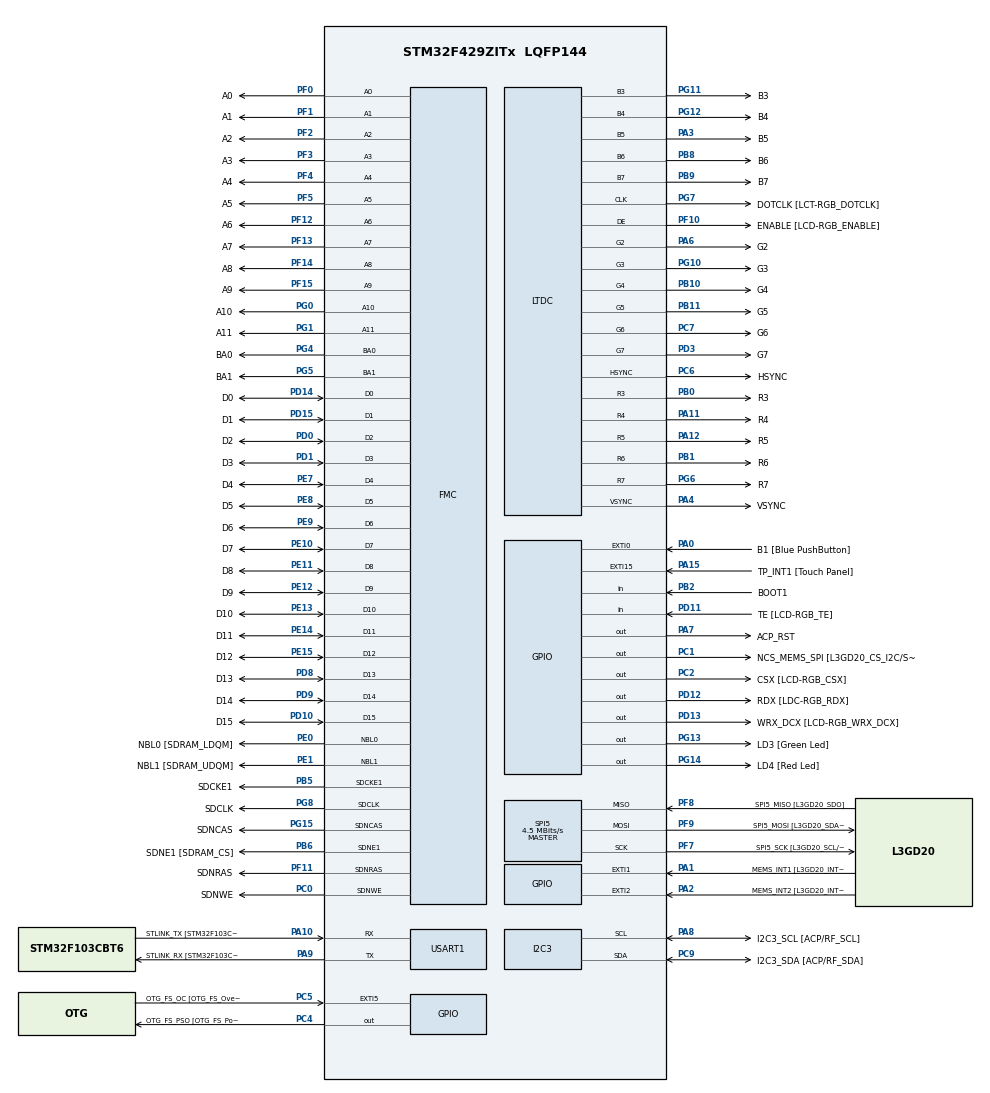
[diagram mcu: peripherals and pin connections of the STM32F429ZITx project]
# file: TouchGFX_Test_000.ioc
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DMA2D.ColorMode=DMA2D_OUTPUT_RGB565
FMC.CASLatency1=FMC_SDRAM_CAS_LATENCY_3
FMC.ExitSelfRefreshDelay1=7
FMC.LoadToActiveDelay1=2
FMC.RCDDelay1=2
FMC.RPDelay1=2
FMC.RPDelay2=2
FMC.ReadBurst1=FMC_SDRAM_RBURST_DISABLE
FMC.ReadPipeDelay1=FMC_SDRAM_RPIPE_DELAY_1
FMC.ReadPipeDelay2=FMC_SDRAM_RPIPE_DELAY_1
FMC.RowCycleDelay1=7
FMC.RowCycleDelay2=7
FMC.SDClockPeriod1=FMC_SDRAM_CLOCK_PERIOD_2
FMC.SDClockPeriod2=FMC_SDRAM_CLOCK_PERIOD_2
FMC.SelfRefreshTime1=4
FMC.WriteRecoveryTime1=3
FREERTOS.Tasks01=defaultTask,0,4096,StartDefaultTask,Default,NULL,Dynamic,NULL,NULL
FREERTOS.configCHECK_FOR_STACK_OVERFLOW=2
FREERTOS.configTOTAL_HEAP_SIZE=32768
FREERTOS.configUSE_APPLICATION_TASK_TAG=1
FREERTOS.configUSE_COUNTING_SEMAPHORES=1
FREERTOS.configUSE_IDLE_HOOK=1
FREERTOS.configUSE_MALLOC_FAILED_HOOK=1
FREERTOS.configUSE_RECURSIVE_MUTEXES=1
LTDC.ActiveH=320
LTDC.ActiveW=240
LTDC.Alpha_L0=255
LTDC.BlendingFactor1_L0=LTDC_BLENDING_FACTOR1_CA
LTDC.BlendingFactor2_L0=LTDC_BLENDING_FACTOR2_CA
LTDC.FBStartAdress_L0=0xD0000000
LTDC.HBP=20
LTDC.HFP=10
LTDC.HSync=10
LTDC.ImageHeight_L0=320
LTDC.ImageWidth_L0=240
LTDC.Layers=0
LTDC.PixelFormat_L0=LTDC_PIXEL_FORMAT_RGB565
LTDC.VFP=4
LTDC.VSync=2
LTDC.WindowX1_L0=240
LTDC.WindowY1_L0=320
Mcu.Family=STM32F4
Mcu.Name=STM32F429ZITx
Mcu.Package=LQFP144
NVIC.DMA2D_IRQn=true\:5\:0\:true\:false\:true\:true\:true\:true
NVIC.LTDC_IRQn=true\:5\:0\:true\:false\:true\:true\:true\:true
NVIC.PriorityGroup=NVIC_PRIORITYGROUP_4
NVIC.TIM6_DAC_IRQn=true\:0\:0\:false\:false\:true\:false\:false\:true
NVIC.TimeBase=TIM6_DAC_IRQn
NVIC.TimeBaseIP=TIM6
PA0/WKUP.GPIO_Label=B1 [Blue PushButton]
PA0/WKUP.GPIO_ModeDefaultEXTI=GPIO_MODE_EVT_RISING
PA0/WKUP.GPIO_PuPd=GPIO_NOPULL
PA0/WKUP.Signal=GPXTI0
PA1.GPIO_Label=MEMS_INT1 [L3GD20_INT1]
PA1.GPIO_ModeDefaultEXTI=GPIO_MODE_EVT_RISING
PA1.GPIO_PuPd=GPIO_NOPULL
PA1.Signal=GPXTI1
PA10.GPIO_Label=STLINK_TX [STM32F103CBT6_PA2]
PA10.Mode=Asynchronous
PA10.Signal=USART1_RX
PA11.GPIO_Label=R4
PA11.GPIO_Mode=GPIO_MODE_AF_PP
PA11.GPIO_PuPd=GPIO_NOPULL
PA11.GPIO_Speed=GPIO_SPEED_FREQ_LOW
PA11.Mode=RGB565
PA11.Signal=LTDC_R4
PA12.GPIO_Label=R5
PA12.GPIO_Mode=GPIO_MODE_AF_PP
PA12.GPIO_PuPd=GPIO_NOPULL
PA12.GPIO_Speed=GPIO_SPEED_FREQ_LOW
PA12.Mode=RGB565
PA12.Signal=LTDC_R5
PA13.GPIO_Label=SWDIO
PA13.Mode=Serial_Wire
PA13.Signal=SYS_JTMS-SWDIO
PA14.GPIO_Label=SWCLK
PA14.Mode=Serial_Wire
PA14.Signal=SYS_JTCK-SWCLK
PA15.GPIO_Label=TP_INT1 [Touch Panel]
PA15.GPIO_ModeDefaultEXTI=GPIO_MODE_EVT_RISING
PA15.GPIO_PuPd=GPIO_NOPULL
PA15.Signal=GPXTI15
PA2.GPIO_Label=MEMS_INT2 [L3GD20_INT2]
PA2.GPIO_ModeDefaultEXTI=GPIO_MODE_EVT_RISING
PA2.GPIO_PuPd=GPIO_NOPULL
PA2.Signal=GPXTI2
PA3.GPIO_Label=B5
PA3.GPIO_Mode=GPIO_MODE_AF_PP
PA3.GPIO_PuPd=GPIO_NOPULL
PA3.GPIO_Speed=GPIO_SPEED_FREQ_LOW
PA3.Mode=RGB565
PA3.Signal=LTDC_B5
PA4.GPIO_Label=VSYNC
PA4.GPIO_Mode=GPIO_MODE_AF_PP
PA4.GPIO_PuPd=GPIO_NOPULL
PA4.GPIO_Speed=GPIO_SPEED_FREQ_LOW
PA4.Mode=RGB565
PA4.Signal=LTDC_VSYNC
PA6.GPIO_Label=G2
PA6.GPIO_Mode=GPIO_MODE_AF_PP
PA6.GPIO_PuPd=GPIO_NOPULL
PA6.GPIO_Speed=GPIO_SPEED_FREQ_LOW
PA6.Mode=RGB565
PA6.Signal=LTDC_G2
PA7.GPIO_Label=ACP_RST
PA7.GPIO_Mode=GPIO_MODE_OUTPUT_PP
PA7.GPIO_PuPd=GPIO_NOPULL
PA7.GPIO_Speed=GPIO_SPEED_FREQ_LOW
PA7.Signal=GPIO_Output
PA8.GPIO_Label=I2C3_SCL [ACP/RF_SCL]
PA8.GPIO_Mode=GPIO_MODE_AF_OD
PA8.GPIO_Pu=GPIO_PULLUP
PA8.GPIO_PuPd=GPIO_NOPULL
PA8.GPIO_Speed=GPIO_SPEED_FREQ_LOW
PA8.Mode=I2C
PA8.Signal=I2C3_SCL
PA9.GPIO_Label=STLINK_RX [STM32F103CBT6_PA3]
PA9.Mode=Asynchronous
PA9.Signal=USART1_TX
PB0.GPIO_Label=R3
PB0.GPIO_Mode=GPIO_MODE_AF_PP
PB0.GPIO_PuPd=GPIO_NOPULL
PB0.GPIO_Speed=GPIO_SPEED_FREQ_LOW
PB0.Mode=RGB565
PB0.Signal=LTDC_R3
PB1.GPIO_Label=R6
PB1.GPIO_Mode=GPIO_MODE_AF_PP
PB1.GPIO_PuPd=GPIO_NOPULL
PB1.GPIO_Speed=GPIO_SPEED_FREQ_LOW
PB1.Mode=RGB565
PB1.Signal=LTDC_R6
PB10.GPIO_Label=G4
PB10.GPIO_Mode=GPIO_MODE_AF_PP
PB10.GPIO_PuPd=GPIO_NOPULL
PB10.GPIO_Speed=GPIO_SPEED_FREQ_LOW
PB10.Mode=RGB565
PB10.Signal=LTDC_G4
PB11.GPIO_Label=G5
PB11.GPIO_Mode=GPIO_MODE_AF_PP
PB11.GPIO_PuPd=GPIO_NOPULL
PB11.GPIO_Speed=GPIO_SPEED_FREQ_LOW
PB11.Mode=RGB565
PB11.Signal=LTDC_G5
PB12.GPIO_Label=OTG_HS_ID
PB12.GPIO_Mode=GPIO_MODE_AF_PP
PB12.GPIO_PuPd=GPIO_NOPULL
PB12.GPIO_Speed=GPIO_SPEED_FREQ_LOW
PB12.Signal=USB_OTG_HS_ID
PB13.GPIO_Label=VBUS_HS
PB13.GPIO_Mode=GPIO_MODE_INPUT
PB13.GPIO_PuPd=GPIO_NOPULL
PB13.Signal=USB_OTG_HS_VBUS
PB14.GPIO_Label=OTG_HS_DM
PB14.GPIO_Mode=GPIO_MODE_AF_PP
PB14.GPIO_PuPd=GPIO_NOPULL
PB14.GPIO_Speed=GPIO_SPEED_FREQ_LOW
PB14.Signal=USB_OTG_HS_DM
PB15.GPIO_Label=OTG_HS_DP
PB15.GPIO_Mode=GPIO_MODE_AF_PP
PB15.GPIO_PuPd=GPIO_NOPULL
PB15.GPIO_Speed=GPIO_SPEED_FREQ_LOW
PB15.Signal=USB_OTG_HS_DP
PB2/BOOT1.GPIO_Label=BOOT1
PB2/BOOT1.GPIO_Mode=GPIO_MODE_INPUT
PB2/BOOT1.GPIO_PuPd=GPIO_NOPULL
PB2/BOOT1.Signal=GPIO_Input
PB5.GPIO_Label=SDCKE1
PB5.GPIO_Mode=GPIO_MODE_AF_PP
PB5.GPIO_PuPd=GPIO_NOPULL
PB5.GPIO_Speed=GPIO_SPEED_FREQ_VERY_HIGH
PB5.Mode=SdramChipSelect2_1
PB5.Signal=FMC_SDCKE1
PB6.GPIO_Label=SDNE1 [SDRAM_CS]
PB6.GPIO_Mode=GPIO_MODE_AF_PP
PB6.GPIO_PuPd=GPIO_NOPULL
PB6.GPIO_Speed=GPIO_SPEED_FREQ_VERY_HIGH
PB6.Mode=SdramChipSelect2_1
PB6.Signal=FMC_SDNE1
PB8.GPIO_Label=B6
PB8.GPIO_Mode=GPIO_MODE_AF_PP
PB8.GPIO_PuPd=GPIO_NOPULL
PB8.GPIO_Speed=GPIO_SPEED_FREQ_LOW
PB8.Mode=RGB565
PB8.Signal=LTDC_B6
PB9.GPIO_Label=B7
PB9.GPIO_Mode=GPIO_MODE_AF_PP
PB9.GPIO_PuPd=GPIO_NOPULL
PB9.GPIO_Speed=GPIO_SPEED_FREQ_LOW
PB9.Mode=RGB565
PB9.Signal=LTDC_B7
PC0.GPIO_Label=SDNWE
PC0.GPIO_Mode=GPIO_MODE_AF_PP
PC0.GPIO_PuPd=GPIO_NOPULL
PC0.GPIO_Speed=GPIO_SPEED_FREQ_VERY_HIGH
PC0.Signal=FMC_SDNWE
PC1.GPIO_Label=NCS_MEMS_SPI [L3GD20_CS_I2C/SPI]
PC1.GPIO_Mode=GPIO_MODE_OUTPUT_PP
PC1.GPIO_PuPd=GPIO_NOPULL
PC1.GPIO_Speed=GPIO_SPEED_FREQ_LOW
PC1.Signal=GPIO_Output
PC10.GPIO_Label=R2
PC10.GPIO_Mode=GPIO_MODE_AF_PP
PC10.GPIO_PuPd=GPIO_NOPULL
PC10.GPIO_Speed=GPIO_SPEED_FREQ_LOW
PC10.Signal=LTDC_R2
PC14/OSC32_IN.GPIO_Label=PC14-OSC32_IN
PC14/OSC32_IN.Signal=RCC_OSC32_IN
PC15/OSC32_OUT.GPIO_Label=PC15-OSC32_OUT
PC15/OSC32_OUT.Signal=RCC_OSC32_OUT
PC2.GPIO_Label=CSX [LCD-RGB_CSX]
PC2.GPIO_Mode=GPIO_MODE_OUTPUT_PP
PC2.GPIO_PuPd=GPIO_NOPULL
PC2.GPIO_Speed=GPIO_SPEED_FREQ_LOW
PC2.Signal=GPIO_Output
PC4.GPIO_Label=OTG_FS_PSO [OTG_FS_PowerSwitchOn]
PC4.GPIO_Mode=GPIO_MODE_OUTPUT_PP
PC4.GPIO_PuPd=GPIO_NOPULL
PC4.GPIO_Speed=GPIO_SPEED_FREQ_LOW
PC4.Signal=GPIO_Output
PC5.GPIO_Label=OTG_FS_OC [OTG_FS_OverCurrent]
PC5.GPIO_ModeDefaultEXTI=GPIO_MODE_EVT_RISING
PC5.Signal=GPXTI5
PC6.GPIO_Label=HSYNC
PC6.GPIO_Mode=GPIO_MODE_AF_PP
PC6.GPIO_PuPd=GPIO_NOPULL
PC6.GPIO_Speed=GPIO_SPEED_FREQ_LOW
PC6.Mode=RGB565
PC6.Signal=LTDC_HSYNC
PC7.GPIO_Label=G6
PC7.GPIO_Mode=GPIO_MODE_AF_PP
PC7.GPIO_PuPd=GPIO_NOPULL
PC7.GPIO_Speed=GPIO_SPEED_FREQ_LOW
PC7.Mode=RGB565
PC7.Signal=LTDC_G6
PC9.GPIO_Label=I2C3_SDA [ACP/RF_SDA]
PC9.GPIO_Mode=GPIO_MODE_AF_OD
PC9.GPIO_Pu=GPIO_PULLUP
PC9.GPIO_PuPd=GPIO_NOPULL
PC9.GPIO_Speed=GPIO_SPEED_FREQ_LOW
PC9.Mode=I2C
PC9.Signal=I2C3_SDA
PD0.GPIO_Label=D2
PD0.GPIO_Mode=GPIO_MODE_AF_PP
PD0.GPIO_PuPd=GPIO_NOPULL
PD0.GPIO_Speed=GPIO_SPEED_FREQ_VERY_HIGH
PD0.Signal=FMC_D2_DA2
PD1.GPIO_Label=D3
PD1.GPIO_Mode=GPIO_MODE_AF_PP
PD1.GPIO_PuPd=GPIO_NOPULL
PD1.GPIO_Speed=GPIO_SPEED_FREQ_VERY_HIGH
PD1.Signal=FMC_D3_DA3
PD10.GPIO_Label=D15
PD10.GPIO_Mode=GPIO_MODE_AF_PP
PD10.GPIO_PuPd=GPIO_NOPULL
PD10.GPIO_Speed=GPIO_SPEED_FREQ_VERY_HIGH
PD10.Signal=FMC_D15_DA15
PD11.GPIO_Label=TE [LCD-RGB_TE]
PD11.GPIO_Mode=GPIO_MODE_INPUT
PD11.GPIO_PuPd=GPIO_NOPULL
PD11.Signal=GPIO_Input
PD12.GPIO_Label=RDX [LDC-RGB_RDX]
PD12.GPIO_Mode=GPIO_MODE_OUTPUT_PP
PD12.GPIO_PuPd=GPIO_NOPULL
PD12.GPIO_Speed=GPIO_SPEED_FREQ_LOW
PD12.Signal=GPIO_Output
PD13.GPIO_Label=WRX_DCX [LCD-RGB_WRX_DCX]
PD13.GPIO_Mode=GPIO_MODE_OUTPUT_PP
PD13.GPIO_PuPd=GPIO_NOPULL
PD13.GPIO_Speed=GPIO_SPEED_FREQ_LOW
PD13.Signal=GPIO_Output
PD14.GPIO_Label=D0
PD14.GPIO_Mode=GPIO_MODE_AF_PP
PD14.GPIO_PuPd=GPIO_NOPULL
PD14.GPIO_Speed=GPIO_SPEED_FREQ_VERY_HIGH
PD14.Signal=FMC_D0_DA0
PD15.GPIO_Label=D1
PD15.GPIO_Mode=GPIO_MODE_AF_PP
PD15.GPIO_PuPd=GPIO_NOPULL
PD15.GPIO_Speed=GPIO_SPEED_FREQ_VERY_HIGH
PD15.Signal=FMC_D1_DA1
PD3.GPIO_Label=G7
PD3.GPIO_Mode=GPIO_MODE_AF_PP
PD3.GPIO_PuPd=GPIO_NOPULL
PD3.GPIO_Speed=GPIO_SPEED_FREQ_LOW
PD3.Mode=RGB565
PD3.Signal=LTDC_G7
PD6.GPIO_Label=B2
PD6.GPIO_Mode=GPIO_MODE_AF_PP
PD6.GPIO_PuPd=GPIO_NOPULL
PD6.GPIO_Speed=GPIO_SPEED_FREQ_LOW
PD6.Signal=LTDC_B2
PD8.GPIO_Label=D13
PD8.GPIO_Mode=GPIO_MODE_AF_PP
PD8.GPIO_PuPd=GPIO_NOPULL
PD8.GPIO_Speed=GPIO_SPEED_FREQ_VERY_HIGH
PD8.Signal=FMC_D13_DA13
PD9.GPIO_Label=D14
PD9.GPIO_Mode=GPIO_MODE_AF_PP
PD9.GPIO_PuPd=GPIO_NOPULL
PD9.GPIO_Speed=GPIO_SPEED_FREQ_VERY_HIGH
PD9.Signal=FMC_D14_DA14
PE0.GPIO_Label=NBL0 [SDRAM_LDQM]
PE0.GPIO_Mode=GPIO_MODE_AF_PP
PE0.GPIO_PuPd=GPIO_NOPULL
PE0.GPIO_Speed=GPIO_SPEED_FREQ_VERY_HIGH
PE0.Signal=FMC_NBL0
PE1.GPIO_Label=NBL1 [SDRAM_UDQM]
PE1.GPIO_Mode=GPIO_MODE_AF_PP
PE1.GPIO_PuPd=GPIO_NOPULL
PE1.GPIO_Speed=GPIO_SPEED_FREQ_VERY_HIGH
PE1.Signal=FMC_NBL1
PE10.GPIO_Label=D7
PE10.GPIO_Mode=GPIO_MODE_AF_PP
PE10.GPIO_PuPd=GPIO_NOPULL
PE10.GPIO_Speed=GPIO_SPEED_FREQ_VERY_HIGH
PE10.Signal=FMC_D7_DA7
PE11.GPIO_Label=D8
PE11.GPIO_Mode=GPIO_MODE_AF_PP
PE11.GPIO_PuPd=GPIO_NOPULL
PE11.GPIO_Speed=GPIO_SPEED_FREQ_VERY_HIGH
PE11.Signal=FMC_D8_DA8
PE12.GPIO_Label=D9
PE12.GPIO_Mode=GPIO_MODE_AF_PP
PE12.GPIO_PuPd=GPIO_NOPULL
PE12.GPIO_Speed=GPIO_SPEED_FREQ_VERY_HIGH
PE12.Signal=FMC_D9_DA9
PE13.GPIO_Label=D10
PE13.GPIO_Mode=GPIO_MODE_AF_PP
PE13.GPIO_PuPd=GPIO_NOPULL
PE13.GPIO_Speed=GPIO_SPEED_FREQ_VERY_HIGH
PE13.Signal=FMC_D10_DA10
PE14.GPIO_Label=D11
PE14.GPIO_Mode=GPIO_MODE_AF_PP
PE14.GPIO_PuPd=GPIO_NOPULL
PE14.GPIO_Speed=GPIO_SPEED_FREQ_VERY_HIGH
PE14.Signal=FMC_D11_DA11
PE15.GPIO_Label=D12
PE15.GPIO_Mode=GPIO_MODE_AF_PP
PE15.GPIO_PuPd=GPIO_NOPULL
PE15.GPIO_Speed=GPIO_SPEED_FREQ_VERY_HIGH
PE15.Signal=FMC_D12_DA12
PE7.GPIO_Label=D4
PE7.GPIO_Mode=GPIO_MODE_AF_PP
PE7.GPIO_PuPd=GPIO_NOPULL
PE7.GPIO_Speed=GPIO_SPEED_FREQ_VERY_HIGH
PE7.Signal=FMC_D4_DA4
PE8.GPIO_Label=D5
PE8.GPIO_Mode=GPIO_MODE_AF_PP
PE8.GPIO_PuPd=GPIO_NOPULL
PE8.GPIO_Speed=GPIO_SPEED_FREQ_VERY_HIGH
PE8.Signal=FMC_D5_DA5
PE9.GPIO_Label=D6
PE9.GPIO_Mode=GPIO_MODE_AF_PP
PE9.GPIO_PuPd=GPIO_NOPULL
PE9.GPIO_Speed=GPIO_SPEED_FREQ_VERY_HIGH
PE9.Signal=FMC_D6_DA6
PF0.GPIO_Label=A0
PF0.GPIO_Mode=GPIO_MODE_AF_PP
PF0.GPIO_PuPd=GPIO_NOPULL
PF0.GPIO_Speed=GPIO_SPEED_FREQ_VERY_HIGH
PF0.Signal=FMC_A0
PF1.GPIO_Label=A1
PF1.GPIO_Mode=GPIO_MODE_AF_PP
PF1.GPIO_PuPd=GPIO_NOPULL
PF1.GPIO_Speed=GPIO_SPEED_FREQ_VERY_HIGH
PF1.Signal=FMC_A1
PF10.GPIO_Label=ENABLE [LCD-RGB_ENABLE]
PF10.GPIO_Mode=GPIO_MODE_AF_PP
PF10.GPIO_PuPd=GPIO_NOPULL
PF10.GPIO_Speed=GPIO_SPEED_FREQ_LOW
PF10.Mode=RGB565
PF10.Signal=LTDC_DE
PF11.GPIO_Label=SDNRAS
PF11.GPIO_Mode=GPIO_MODE_AF_PP
PF11.GPIO_PuPd=GPIO_NOPULL
PF11.GPIO_Speed=GPIO_SPEED_FREQ_VERY_HIGH
PF11.Signal=FMC_SDNRAS
PF12.GPIO_Label=A6
PF12.GPIO_Mode=GPIO_MODE_AF_PP
PF12.GPIO_PuPd=GPIO_NOPULL
PF12.GPIO_Speed=GPIO_SPEED_FREQ_VERY_HIGH
PF12.Signal=FMC_A6
PF13.GPIO_Label=A7
PF13.GPIO_Mode=GPIO_MODE_AF_PP
PF13.GPIO_PuPd=GPIO_NOPULL
PF13.GPIO_Speed=GPIO_SPEED_FREQ_VERY_HIGH
PF13.Signal=FMC_A7
PF14.GPIO_Label=A8
PF14.GPIO_Mode=GPIO_MODE_AF_PP
PF14.GPIO_PuPd=GPIO_NOPULL
PF14.GPIO_Speed=GPIO_SPEED_FREQ_VERY_HIGH
PF14.Signal=FMC_A8
PF15.GPIO_Label=A9
PF15.GPIO_Mode=GPIO_MODE_AF_PP
PF15.GPIO_PuPd=GPIO_NOPULL
PF15.GPIO_Speed=GPIO_SPEED_FREQ_VERY_HIGH
PF15.Signal=FMC_A9
PF2.GPIO_Label=A2
PF2.GPIO_Mode=GPIO_MODE_AF_PP
PF2.GPIO_PuPd=GPIO_NOPULL
PF2.GPIO_Speed=GPIO_SPEED_FREQ_VERY_HIGH
PF2.Signal=FMC_A2
PF3.GPIO_Label=A3
PF3.GPIO_Mode=GPIO_MODE_AF_PP
PF3.GPIO_PuPd=GPIO_NOPULL
PF3.GPIO_Speed=GPIO_SPEED_FREQ_VERY_HIGH
PF3.Signal=FMC_A3
PF4.GPIO_Label=A4
PF4.GPIO_Mode=GPIO_MODE_AF_PP
PF4.GPIO_PuPd=GPIO_NOPULL
PF4.GPIO_Speed=GPIO_SPEED_FREQ_VERY_HIGH
PF4.Signal=FMC_A4
PF5.GPIO_Label=A5
PF5.GPIO_Mode=GPIO_MODE_AF_PP
PF5.GPIO_PuPd=GPIO_NOPULL
PF5.GPIO_Speed=GPIO_SPEED_FREQ_VERY_HIGH
PF5.Signal=FMC_A5
PF7.GPIO_Label=SPI5_SCK [L3GD20_SCL/SPC]
PF7.GPIO_Mode=GPIO_MODE_AF_PP
PF7.GPIO_PuPd=GPIO_NOPULL
PF7.GPIO_Speed=GPIO_SPEED_FREQ_LOW
PF7.Mode=Full_Duplex_Master
PF7.Signal=SPI5_SCK
PF8.GPIO_Label=SPI5_MISO [L3GD20_SDO]
PF8.GPIO_Mode=GPIO_MODE_AF_PP
PF8.GPIO_PuPd=GPIO_NOPULL
PF8.GPIO_Speed=GPIO_SPEED_FREQ_LOW
PF8.Mode=Full_Duplex_Master
PF8.Signal=SPI5_MISO
PF9.GPIO_Label=SPI5_MOSI [L3GD20_SDA/SDI/SDO]
PF9.GPIO_Mode=GPIO_MODE_AF_PP
PF9.GPIO_PuPd=GPIO_NOPULL
PF9.GPIO_Speed=GPIO_SPEED_FREQ_LOW
PF9.Mode=Full_Duplex_Master
PF9.Signal=SPI5_MOSI
PG0.GPIO_Label=A10
PG0.GPIO_Mode=GPIO_MODE_AF_PP
PG0.GPIO_PuPd=GPIO_NOPULL
PG0.GPIO_Speed=GPIO_SPEED_FREQ_VERY_HIGH
PG0.Signal=FMC_A10
PG1.GPIO_Label=A11
PG1.GPIO_Mode=GPIO_MODE_AF_PP
PG1.GPIO_PuPd=GPIO_NOPULL
PG1.GPIO_Speed=GPIO_SPEED_FREQ_VERY_HIGH
PG1.Signal=FMC_A11
PG10.GPIO_Label=G3
PG10.GPIO_Mode=GPIO_MODE_AF_PP
PG10.GPIO_PuPd=GPIO_NOPULL
PG10.GPIO_Speed=GPIO_SPEED_FREQ_LOW
PG10.Mode=RGB565
PG10.Signal=LTDC_G3
PG11.GPIO_Label=B3
PG11.GPIO_Mode=GPIO_MODE_AF_PP
PG11.GPIO_PuPd=GPIO_NOPULL
PG11.GPIO_Speed=GPIO_SPEED_FREQ_LOW
PG11.Mode=RGB565
PG11.Signal=LTDC_B3
PG12.GPIO_Label=B4
PG12.GPIO_Mode=GPIO_MODE_AF_PP
PG12.GPIO_PuPd=GPIO_NOPULL
PG12.GPIO_Speed=GPIO_SPEED_FREQ_LOW
PG12.Mode=RGB565
PG12.Signal=LTDC_B4
PG13.GPIO_Label=LD3 [Green Led]
PG13.GPIO_Mode=GPIO_MODE_OUTPUT_PP
PG13.GPIO_PuPd=GPIO_NOPULL
PG13.GPIO_Speed=GPIO_SPEED_FREQ_LOW
PG13.Signal=GPIO_Output
PG14.GPIO_Label=LD4 [Red Led]
PG14.GPIO_Mode=GPIO_MODE_OUTPUT_PP
PG14.GPIO_PuPd=GPIO_NOPULL
PG14.GPIO_Speed=GPIO_SPEED_FREQ_LOW
PG14.Signal=GPIO_Output
PG15.GPIO_Label=SDNCAS
PG15.GPIO_Mode=GPIO_MODE_AF_PP
PG15.GPIO_PuPd=GPIO_NOPULL
PG15.GPIO_Speed=GPIO_SPEED_FREQ_VERY_HIGH
PG15.Signal=FMC_SDNCAS
PG4.GPIO_Label=BA0
PG4.GPIO_Mode=GPIO_MODE_AF_PP
PG4.GPIO_PuPd=GPIO_NOPULL
PG4.GPIO_Speed=GPIO_SPEED_FREQ_VERY_HIGH
PG4.Signal=FMC_A14_BA0
PG5.GPIO_Label=BA1
PG5.GPIO_Mode=GPIO_MODE_AF_PP
PG5.GPIO_PuPd=GPIO_NOPULL
PG5.GPIO_Speed=GPIO_SPEED_FREQ_VERY_HIGH
PG5.Signal=FMC_A15_BA1
PG6.GPIO_Label=R7
PG6.GPIO_Mode=GPIO_MODE_AF_PP
PG6.GPIO_PuPd=GPIO_NOPULL
PG6.GPIO_Speed=GPIO_SPEED_FREQ_LOW
PG6.Mode=RGB565
PG6.Signal=LTDC_R7
PG7.GPIO_Label=DOTCLK [LCT-RGB_DOTCLK]
PG7.GPIO_Mode=GPIO_MODE_AF_PP
PG7.GPIO_PuPd=GPIO_NOPULL
PG7.GPIO_Speed=GPIO_SPEED_FREQ_LOW
PG7.Mode=RGB565
PG7.Signal=LTDC_CLK
PG8.GPIO_Label=SDCLK
PG8.GPIO_Mode=GPIO_MODE_AF_PP
PG8.GPIO_PuPd=GPIO_NOPULL
PG8.GPIO_Speed=GPIO_SPEED_FREQ_VERY_HIGH
PG8.Signal=FMC_SDCLK
PH0/OSC_IN.GPIO_Label=PH0-OSC_IN
PH0/OSC_IN.Mode=HSE-External-Oscillator
PH0/OSC_IN.Signal=RCC_OSC_IN
PH1/OSC_OUT.GPIO_Label=PH1-OSC_OUT
PH1/OSC_OUT.Mode=HSE-External-Oscillator
PH1/OSC_OUT.Signal=RCC_OSC_OUT
ProjectManager.HeapSize=0x200
ProjectManager.StackSize=0x400
ProjectManager.TargetToolchain=STM32CubeIDE
RCC.48MHZClocksFreq_Value=48000000
RCC.AHBFreq_Value=72000000
RCC.APB1CLKDivider=RCC_HCLK_DIV2
RCC.APB1Freq_Value=36000000
RCC.APB1TimFreq_Value=72000000
RCC.APB2Freq_Value=72000000
RCC.APB2TimFreq_Value=72000000
RCC.CortexFreq_Value=72000000
RCC.HCLKFreq_Value=72000000
RCC.HSE_VALUE=8000000
RCC.HSI_VALUE=16000000
RCC.LSE_VALUE=32768
RCC.PLLN=72
RCC.PLLQ=3
RCC.PLLSAIR=2
RCC.PLLSourceVirtual=RCC_PLLSOURCE_HSE
RCC.SYSCLKFreq_VALUE=72000000
RCC.SYSCLKSource=RCC_SYSCLKSOURCE_PLLCLK
RCC.VCOOutputFreq_Value=144000000
SH.FMC_A0.0=FMC_A0,12b-sda1
SH.FMC_A1.0=FMC_A1,12b-sda1
SH.FMC_A10.0=FMC_A10,12b-sda1
SH.FMC_A11.0=FMC_A11,12b-sda1
SH.FMC_A14_BA0.0=FMC_BA0,FourSdramBanks1
SH.FMC_A15_BA1.0=FMC_BA1,FourSdramBanks1
SH.FMC_A2.0=FMC_A2,12b-sda1
SH.FMC_A3.0=FMC_A3,12b-sda1
SH.FMC_A4.0=FMC_A4,12b-sda1
SH.FMC_A5.0=FMC_A5,12b-sda1
SH.FMC_A6.0=FMC_A6,12b-sda1
SH.FMC_A7.0=FMC_A7,12b-sda1
SH.FMC_A8.0=FMC_A8,12b-sda1
SH.FMC_A9.0=FMC_A9,12b-sda1
SH.FMC_D0_DA0.0=FMC_D0,sd-16b-d1
SH.FMC_D10_DA10.0=FMC_D10,sd-16b-d1
SH.FMC_D11_DA11.0=FMC_D11,sd-16b-d1
SH.FMC_D12_DA12.0=FMC_D12,sd-16b-d1
SH.FMC_D13_DA13.0=FMC_D13,sd-16b-d1
SH.FMC_D14_DA14.0=FMC_D14,sd-16b-d1
SH.FMC_D15_DA15.0=FMC_D15,sd-16b-d1
SH.FMC_D1_DA1.0=FMC_D1,sd-16b-d1
SH.FMC_D2_DA2.0=FMC_D2,sd-16b-d1
SH.FMC_D3_DA3.0=FMC_D3,sd-16b-d1
SH.FMC_D4_DA4.0=FMC_D4,sd-16b-d1
SH.FMC_D5_DA5.0=FMC_D5,sd-16b-d1
SH.FMC_D6_DA6.0=FMC_D6,sd-16b-d1
SH.FMC_D7_DA7.0=FMC_D7,sd-16b-d1
SH.FMC_D8_DA8.0=FMC_D8,sd-16b-d1
SH.FMC_D9_DA9.0=FMC_D9,sd-16b-d1
SH.FMC_NBL0.0=FMC_NBL0,Sd2ByteEnable1
SH.FMC_NBL1.0=FMC_NBL1,Sd2ByteEnable1
SH.FMC_SDCLK.0=FMC_SDCLK,12b-sda1
SH.FMC_SDNCAS.0=FMC_SDNCAS,12b-sda1
SH.FMC_SDNRAS.0=FMC_SDNRAS,12b-sda1
SH.FMC_SDNWE.0=FMC_SDNWE,12b-sda1
SPI5.BaudRatePrescaler=SPI_BAUDRATEPRESCALER_16
SPI5.CalculateBaudRate=4.5 MBits/s
SPI5.Direction=SPI_DIRECTION_2LINES
SPI5.Mode=SPI_MODE_MASTER
SPI5.VirtualType=VM_MASTER
STMicroelectronics.X-CUBE-TOUCHGFX.4.17.0.ApplicationCcGraphicsJjApplication=TouchGFXOoGenerator
STMicroelectronics.X-CUBE-TOUCHGFX.4.17.0.tgfx_display_interface=disp_ltdc
STMicroelectronics.X-CUBE-TOUCHGFX.4.17.0.tgfx_hardware_accelerator=dma_2d
STMicroelectronics.X-CUBE-TOUCHGFX.4.17.0.tgfx_vsync=vsync_ltdc
STMicroelectronics.X-CUBE-TOUCHGFX.4.17.0_IsPackSelfContextualization=true
USART1.VirtualMode=VM_ASYNC
VP_CRC_VS_CRC.Mode=CRC_Activate
VP_DMA2D_VS_DMA2D.Mode=DMA2D_Activate
VP_FREERTOS_VS_CMSIS_V1.Mode=CMSIS_V1
VP_STMicroelectronics.X-CUBE-TOUCHGFX_VS_GraphicsJjApplication_4.17.0.Mode=GraphicsJjApplication
VP_SYS_VS_tim6.Mode=TIM6
VP_TIM1_VS_ClockSourceINT.Mode=Internal
board=STM32F429I-DISC1

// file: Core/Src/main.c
/* USER CODE BEGIN Header */
/**
  ******************************************************************************
  * @file           : main.c
  * @brief          : Main program body
  ******************************************************************************
  * @attention
  *
  * <h2><center>&copy; Copyright (c) 2021 STMicroelectronics.
  * All rights reserved.</center></h2>
  *
  * This software component is licensed by ST under Ultimate Liberty license
  * SLA0044, the "License"; You may not use this file except in compliance with
  * the License. You may obtain a copy of the License at:
  *                             www.st.com/SLA0044
  *
  ******************************************************************************
  */
/* USER CODE END Header */
#include "main.h"
#include "cmsis_os.h"
#include "crc.h"
#include "dma2d.h"
#include "i2c.h"
#include "ltdc.h"
#include "spi.h"
#include "tim.h"
#include "usart.h"
#include "gpio.h"
#include "fmc.h"
#include "app_touchgfx.h"

/* USER CODE BEGIN Includes */
#include "ili9341/ili9341.h"
#include "Common/lcd.h"
/* USER CODE END Includes */

/* USER CODE BEGIN PV */
static LCD_DrvTypeDef* LcdDrv;
/* USER CODE END PV */

void SystemClock_Config(void);
void MX_FREERTOS_Init(void);

int main(void)
{

  /* MCU Configuration--------------------------------------------------------*/

  /* Reset of all peripherals, Initializes the Flash interface and the Systick. */
  HAL_Init();

  /* Configure the system clock */
  SystemClock_Config();

  /* Initialize all configured peripherals */
  MX_GPIO_Init();
  MX_CRC_Init();
  MX_DMA2D_Init();
  MX_FMC_Init();
  MX_I2C3_Init();
  MX_LTDC_Init();
  MX_SPI5_Init();
  MX_TIM1_Init();
  MX_USART1_UART_Init();
  MX_TouchGFX_Init();
  /* USER CODE BEGIN 2 */
  LcdDrv = &ili9341_drv;
  LcdDrv->Init();
  LcdDrv->DisplayOff();
  /* USER CODE END 2 */

  /* Call init function for freertos objects (in freertos.c) */
  MX_FREERTOS_Init();
  /* Start scheduler */
  osKernelStart();

  /* We should never get here as control is now taken by the scheduler */
  /* Infinite loop */
  while (1)
  {

  }
}

void SystemClock_Config(void)
{
  RCC_OscInitTypeDef RCC_OscInitStruct = {0};
  RCC_ClkInitTypeDef RCC_ClkInitStruct = {0};

  /** Configure the main internal regulator output voltage
  */
  __HAL_RCC_PWR_CLK_ENABLE();
  __HAL_PWR_VOLTAGESCALING_CONFIG(PWR_REGULATOR_VOLTAGE_SCALE3);
  /** Initializes the RCC Oscillators according to the specified parameters
  * in the RCC_OscInitTypeDef structure.
  */
  RCC_OscInitStruct.OscillatorType = RCC_OSCILLATORTYPE_HSE;
  RCC_OscInitStruct.HSEState = RCC_HSE_ON;
  RCC_OscInitStruct.PLL.PLLState = RCC_PLL_ON;
  RCC_OscInitStruct.PLL.PLLSource = RCC_PLLSOURCE_HSE;
  RCC_OscInitStruct.PLL.PLLM = 16;
  RCC_OscInitStruct.PLL.PLLN = 72;
  RCC_OscInitStruct.PLL.PLLP = RCC_PLLP_DIV2;
  RCC_OscInitStruct.PLL.PLLQ = 3;
  if (HAL_RCC_OscConfig(&RCC_OscInitStruct) != HAL_OK)
  {
    Error_Handler();
  }
  /** Initializes the CPU, AHB and APB buses clocks
  */
  RCC_ClkInitStruct.ClockType = RCC_CLOCKTYPE_HCLK|RCC_CLOCKTYPE_SYSCLK
                              |RCC_CLOCKTYPE_PCLK1|RCC_CLOCKTYPE_PCLK2;
  RCC_ClkInitStruct.SYSCLKSource = RCC_SYSCLKSOURCE_PLLCLK;
  RCC_ClkInitStruct.AHBCLKDivider = RCC_SYSCLK_DIV1;
  RCC_ClkInitStruct.APB1CLKDivider = RCC_HCLK_DIV2;
  RCC_ClkInitStruct.APB2CLKDivider = RCC_HCLK_DIV1;

  if (HAL_RCC_ClockConfig(&RCC_ClkInitStruct, FLASH_LATENCY_2) != HAL_OK)
  {
    Error_Handler();
  }
}

void HAL_TIM_PeriodElapsedCallback(TIM_HandleTypeDef *htim)
{
  if (htim->Instance == TIM6) {
    HAL_IncTick();
  }
}

void Error_Handler(void)
{
  __disable_irq();
  while (1)
  {
  }
}

/************************ (C) COPYRIGHT STMicroelectronics *****END OF FILE****/

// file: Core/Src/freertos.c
/* USER CODE BEGIN Header */
/**
  ******************************************************************************
  * File Name          : freertos.c
  * Description        : Code for freertos applications
  ******************************************************************************
  * @attention
  *
  * <h2><center>&copy; Copyright (c) 2021 STMicroelectronics.
  * All rights reserved.</center></h2>
  *
  * This software component is licensed by ST under Ultimate Liberty license
  * SLA0044, the "License"; You may not use this file except in compliance with
  * the License. You may obtain a copy of the License at:
  *                             www.st.com/SLA0044
  *
  ******************************************************************************
  */
/* USER CODE END Header */

#include "FreeRTOS.h"
#include "task.h"
#include "main.h"
#include "cmsis_os.h"

/* USER CODE BEGIN Variables */
osThreadId touchGFXTaskHandle;
/* USER CODE END Variables */
osThreadId defaultTaskHandle;

/* USER CODE BEGIN FunctionPrototypes */
void TouchGFX_Task(void const * argument);
/* USER CODE END FunctionPrototypes */

void StartDefaultTask(void const * argument);

void MX_FREERTOS_Init(void); /* (MISRA C 2004 rule 8.1) */

/* GetIdleTaskMemory prototype (linked to static allocation support) */
void vApplicationGetIdleTaskMemory( StaticTask_t **ppxIdleTaskTCBBuffer, StackType_t **ppxIdleTaskStackBuffer, uint32_t *pulIdleTaskStackSize );

/* Hook prototypes */
void vApplicationIdleHook(void);
void vApplicationStackOverflowHook(xTaskHandle xTask, signed char *pcTaskName);
void vApplicationMallocFailedHook(void);

/* USER CODE BEGIN 2 */
__weak void vApplicationIdleHook( void )
{
   /* vApplicationIdleHook() will only be called if configUSE_IDLE_HOOK is set
   to 1 in FreeRTOSConfig.h. It will be called on each iteration of the idle
   task. It is essential that code added to this hook function never attempts
   to block in any way (for example, call xQueueReceive() with a block time
   specified, or call vTaskDelay()). If the application makes use of the
   vTaskDelete() API function (as this demo application does) then it is also
   important that vApplicationIdleHook() is permitted to return to its calling
   function, because it is the responsibility of the idle task to clean up
   memory allocated by the kernel to any task that has since been deleted. */
}
/* USER CODE END 2 */

/* USER CODE BEGIN 4 */
__weak void vApplicationStackOverflowHook(xTaskHandle xTask, signed char *pcTaskName)
{
   /* Run time stack overflow checking is performed if
   configCHECK_FOR_STACK_OVERFLOW is defined to 1 or 2. This hook function is
   called if a stack overflow is detected. */
}
/* USER CODE END 4 */

/* USER CODE BEGIN 5 */
__weak void vApplicationMallocFailedHook(void)
{
   /* vApplicationMallocFailedHook() will only be called if
   configUSE_MALLOC_FAILED_HOOK is set to 1 in FreeRTOSConfig.h. It is a hook
   function that will get called if a call to pvPortMalloc() fails.
   pvPortMalloc() is called internally by the kernel whenever a task, queue,
   timer or semaphore is created. It is also called by various parts of the
   demo application. If heap_1.c or heap_2.c are used, then the size of the
   heap available to pvPortMalloc() is defined by configTOTAL_HEAP_SIZE in
   FreeRTOSConfig.h, and the xPortGetFreeHeapSize() API function can be used
   to query the size of free heap space that remains (although it does not
   provide information on how the remaining heap might be fragmented). */
}
/* USER CODE END 5 */

/* USER CODE BEGIN GET_IDLE_TASK_MEMORY */
static StaticTask_t xIdleTaskTCBBuffer;
static StackType_t xIdleStack[configMINIMAL_STACK_SIZE];

void vApplicationGetIdleTaskMemory( StaticTask_t **ppxIdleTaskTCBBuffer, StackType_t **ppxIdleTaskStackBuffer, uint32_t *pulIdleTaskStackSize )
{
  *ppxIdleTaskTCBBuffer = &xIdleTaskTCBBuffer;
  *ppxIdleTaskStackBuffer = &xIdleStack[0];
  *pulIdleTaskStackSize = configMINIMAL_STACK_SIZE;
  /* place for user code */
}
/* USER CODE END GET_IDLE_TASK_MEMORY */

void MX_FREERTOS_Init(void) {

  /* Create the thread(s) */
  /* definition and creation of defaultTask */
  osThreadDef(defaultTask, StartDefaultTask, osPriorityNormal, 0, 4096);
  defaultTaskHandle = osThreadCreate(osThread(defaultTask), NULL);

  /* USER CODE BEGIN RTOS_THREADS */
  /* add threads, ... */
  osThreadDef(touchTask, TouchGFX_Task, osPriorityNormal, 0, 4096);
  touchGFXTaskHandle = osThreadCreate(osThread(touchTask), NULL);
  /* USER CODE END RTOS_THREADS */

}

void StartDefaultTask(void const * argument)
{
  /* USER CODE BEGIN StartDefaultTask */
  /* Infinite loop */
  for(;;)
  {
	  HAL_GPIO_TogglePin(GPIOG, GPIO_PIN_13);
	  osDelay(500);
  }
  /* USER CODE END StartDefaultTask */
}

/************************ (C) COPYRIGHT STMicroelectronics *****END OF FILE****/
